VERSION 5.7 ;
  NOWIREEXTENSIONATPIN ON ;
  DIVIDERCHAR "/" ;
  BUSBITCHARS "[]" ;
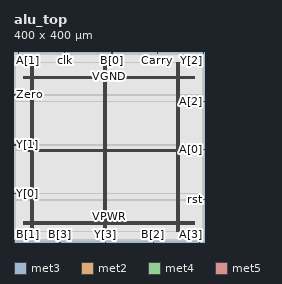
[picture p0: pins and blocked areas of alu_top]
MACRO alu_top
  CLASS BLOCK ;
  FOREIGN alu_top ;
  ORIGIN 0.000 0.000 ;
  SIZE 400.000 BY 400.000 ;
  PIN A[0]
    DIRECTION INPUT ;
    USE SIGNAL ;
    ANTENNAGATEAREA 0.213000 ;
    PORT
      LAYER met3 ;
        RECT 396.000 193.840 400.000 194.440 ;
    END
  END A[0]
  PIN A[1]
    DIRECTION INPUT ;
    USE SIGNAL ;
    ANTENNAGATEAREA 0.247500 ;
    PORT
      LAYER met2 ;
        RECT 9.750 396.000 10.030 400.000 ;
    END
  END A[1]
  PIN A[2]
    DIRECTION INPUT ;
    USE SIGNAL ;
    ANTENNAGATEAREA 0.247500 ;
    PORT
      LAYER met3 ;
        RECT 396.000 295.840 400.000 296.440 ;
    END
  END A[2]
  PIN A[3]
    DIRECTION INPUT ;
    USE SIGNAL ;
    ANTENNAGATEAREA 0.247500 ;
    PORT
      LAYER met2 ;
        RECT 389.710 0.000 389.990 4.000 ;
    END
  END A[3]
  PIN B[0]
    DIRECTION INPUT ;
    USE SIGNAL ;
    ANTENNAGATEAREA 0.159000 ;
    PORT
      LAYER met2 ;
        RECT 206.170 396.000 206.450 400.000 ;
    END
  END B[0]
  PIN B[1]
    DIRECTION INPUT ;
    USE SIGNAL ;
    ANTENNAGATEAREA 0.213000 ;
    PORT
      LAYER met2 ;
        RECT 0.090 0.000 0.370 4.000 ;
    END
  END B[1]
  PIN B[2]
    DIRECTION INPUT ;
    USE SIGNAL ;
    ANTENNAGATEAREA 0.213000 ;
    PORT
      LAYER met2 ;
        RECT 293.110 0.000 293.390 4.000 ;
    END
  END B[2]
  PIN B[3]
    DIRECTION INPUT ;
    USE SIGNAL ;
    ANTENNAGATEAREA 0.213000 ;
    PORT
      LAYER met2 ;
        RECT 96.690 0.000 96.970 4.000 ;
    END
  END B[3]
  PIN Carry
    DIRECTION OUTPUT TRISTATE ;
    USE SIGNAL ;
    ANTENNADIFFAREA 0.795200 ;
    PORT
      LAYER met2 ;
        RECT 302.770 396.000 303.050 400.000 ;
    END
  END Carry
  PIN VGND
    DIRECTION INOUT ;
    USE GROUND ;
    PORT
      LAYER met4 ;
        RECT 39.060 21.520 40.660 378.320 ;
    END
    PORT
      LAYER met4 ;
        RECT 192.660 21.520 194.260 378.320 ;
    END
    PORT
      LAYER met4 ;
        RECT 346.260 21.520 347.860 378.320 ;
    END
    PORT
      LAYER met5 ;
        RECT 20.000 40.910 380.200 42.510 ;
    END
    PORT
      LAYER met5 ;
        RECT 20.000 194.090 380.200 195.690 ;
    END
    PORT
      LAYER met5 ;
        RECT 20.000 347.270 380.200 348.870 ;
    END
  END VGND
  PIN VPWR
    DIRECTION INOUT ;
    USE POWER ;
    PORT
      LAYER met4 ;
        RECT 35.760 21.520 37.360 378.320 ;
    END
    PORT
      LAYER met4 ;
        RECT 189.360 21.520 190.960 378.320 ;
    END
    PORT
      LAYER met4 ;
        RECT 342.960 21.520 344.560 378.320 ;
    END
    PORT
      LAYER met5 ;
        RECT 20.000 37.610 380.200 39.210 ;
    END
    PORT
      LAYER met5 ;
        RECT 20.000 190.790 380.200 192.390 ;
    END
    PORT
      LAYER met5 ;
        RECT 20.000 343.970 380.200 345.570 ;
    END
  END VPWR
  PIN Y[0]
    DIRECTION OUTPUT TRISTATE ;
    USE SIGNAL ;
    ANTENNADIFFAREA 0.795200 ;
    PORT
      LAYER met3 ;
        RECT 0.000 102.040 4.000 102.640 ;
    END
  END Y[0]
  PIN Y[1]
    DIRECTION OUTPUT TRISTATE ;
    USE SIGNAL ;
    ANTENNADIFFAREA 0.795200 ;
    PORT
      LAYER met3 ;
        RECT 0.000 204.040 4.000 204.640 ;
    END
  END Y[1]
  PIN Y[2]
    DIRECTION OUTPUT TRISTATE ;
    USE SIGNAL ;
    ANTENNADIFFAREA 0.795200 ;
    PORT
      LAYER met2 ;
        RECT 399.370 396.000 399.650 400.000 ;
    END
  END Y[2]
  PIN Y[3]
    DIRECTION OUTPUT TRISTATE ;
    USE SIGNAL ;
    ANTENNADIFFAREA 0.795200 ;
    PORT
      LAYER met2 ;
        RECT 193.290 0.000 193.570 4.000 ;
    END
  END Y[3]
  PIN Zero
    DIRECTION OUTPUT TRISTATE ;
    USE SIGNAL ;
    ANTENNADIFFAREA 0.795200 ;
    PORT
      LAYER met3 ;
        RECT 0.000 309.440 4.000 310.040 ;
    END
  END Zero
  PIN clk
    DIRECTION INPUT ;
    USE SIGNAL ;
    ANTENNAGATEAREA 0.852000 ;
    PORT
      LAYER met2 ;
        RECT 106.350 396.000 106.630 400.000 ;
    END
  END clk
  PIN rst
    DIRECTION INPUT ;
    USE SIGNAL ;
    ANTENNAGATEAREA 0.213000 ;
    PORT
      LAYER met3 ;
        RECT 396.000 88.440 400.000 89.040 ;
    END
  END rst
  OBS
      LAYER li1 ;
        RECT 20.240 21.675 379.960 378.165 ;
      LAYER met1 ;
        RECT 0.070 13.980 399.670 378.320 ;
      LAYER met2 ;
        RECT 0.100 395.720 9.470 396.000 ;
        RECT 10.310 395.720 106.070 396.000 ;
        RECT 106.910 395.720 205.890 396.000 ;
        RECT 206.730 395.720 302.490 396.000 ;
        RECT 303.330 395.720 399.090 396.000 ;
        RECT 0.100 4.280 399.640 395.720 ;
        RECT 0.650 3.670 96.410 4.280 ;
        RECT 97.250 3.670 193.010 4.280 ;
        RECT 193.850 3.670 292.830 4.280 ;
        RECT 293.670 3.670 389.430 4.280 ;
        RECT 390.270 3.670 399.640 4.280 ;
      LAYER met3 ;
        RECT 4.000 310.440 396.000 378.245 ;
        RECT 4.400 309.040 396.000 310.440 ;
        RECT 4.000 296.840 396.000 309.040 ;
        RECT 4.000 295.440 395.600 296.840 ;
        RECT 4.000 205.040 396.000 295.440 ;
        RECT 4.400 203.640 396.000 205.040 ;
        RECT 4.000 194.840 396.000 203.640 ;
        RECT 4.000 193.440 395.600 194.840 ;
        RECT 4.000 103.040 396.000 193.440 ;
        RECT 4.400 101.640 396.000 103.040 ;
        RECT 4.000 89.440 396.000 101.640 ;
        RECT 4.000 88.040 395.600 89.440 ;
        RECT 4.000 21.595 396.000 88.040 ;
  END
END alu_top
END LIBRARY

